VERSION 5.7 ;
  DIVIDERCHAR "/" ;
  BUSBITCHARS "[]" ;
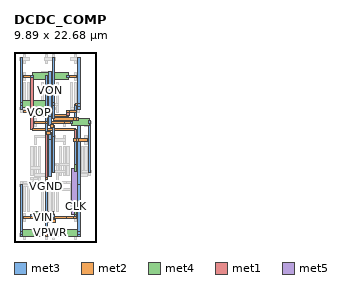
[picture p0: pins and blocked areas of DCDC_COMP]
MACRO DCDC_COMP
  CLASS BLOCK ;
  ORIGIN 0 0 ;
  FOREIGN DCDC_COMP 0 0 ;
  SIZE 9.89 BY 22.68 ;
  PIN VOP
    DIRECTION INOUT ;
    USE SIGNAL ;
    PORT
      LAYER met3 ;
        RECT 3.73 15.38 4.01 19.9 ;
      LAYER met3 ;
        RECT 4.16 7.82 4.44 12.34 ;
      LAYER met2 ;
        RECT 1.12 15.4 2.32 15.68 ;
      LAYER met3 ;
        RECT 3.73 13.02 4.01 15.4 ;
      LAYER met2 ;
        RECT 3.87 12.88 4.3 13.16 ;
      LAYER met3 ;
        RECT 4.16 12.18 4.44 13.02 ;
      LAYER met3 ;
        RECT 3.73 15.215 4.01 15.585 ;
      LAYER met4 ;
        RECT 2.15 15 3.87 15.8 ;
      LAYER met3 ;
        RECT 2.01 15.349 2.29 15.591 ;
      LAYER met2 ;
        RECT 1.99 15.4 2.31 15.68 ;
    END
  END VOP
  PIN VON
    DIRECTION INOUT ;
    USE SIGNAL ;
    PORT
      LAYER met3 ;
        RECT 4.16 15.8 4.44 20.32 ;
      LAYER met3 ;
        RECT 4.59 8.24 4.87 12.76 ;
      LAYER met2 ;
        RECT 6.28 15.4 7.48 15.68 ;
      LAYER met3 ;
        RECT 4.16 13.86 4.44 15.96 ;
      LAYER met2 ;
        RECT 4.3 13.72 4.73 14 ;
      LAYER met3 ;
        RECT 4.59 12.6 4.87 13.86 ;
      LAYER met3 ;
        RECT 4.16 14.935 4.44 15.305 ;
      LAYER met2 ;
        RECT 4.3 14.98 6.45 15.26 ;
      LAYER met1 ;
        RECT 6.325 15.12 6.575 15.54 ;
      LAYER met2 ;
        RECT 6.29 15.4 6.61 15.68 ;
    END
  END VON
  PIN VPWR
    DIRECTION INOUT ;
    USE SIGNAL ;
    PORT
      LAYER met3 ;
        RECT 4.59 16.22 4.87 22 ;
      LAYER met3 ;
        RECT 7.6 0.68 7.88 6.88 ;
      LAYER met3 ;
        RECT 0.72 15.8 1 22 ;
      LAYER met3 ;
        RECT 7.6 15.8 7.88 22 ;
      LAYER met3 ;
        RECT 0.72 0.68 1 6.88 ;
      LAYER met3 ;
        RECT 4.59 14.7 4.87 16.38 ;
      LAYER met2 ;
        RECT 4.73 14.56 7.74 14.84 ;
      LAYER met3 ;
        RECT 7.6 6.72 7.88 14.7 ;
      LAYER met3 ;
        RECT 4.59 16.315 4.87 16.685 ;
      LAYER met4 ;
        RECT 0.86 16.1 4.73 16.9 ;
      LAYER met3 ;
        RECT 0.72 16.315 1 16.685 ;
      LAYER met2 ;
        RECT 7.15 14.56 7.47 14.84 ;
      LAYER met3 ;
        RECT 7.17 14.7 7.45 16.38 ;
      LAYER met2 ;
        RECT 7.31 16.24 7.74 16.52 ;
      LAYER met3 ;
        RECT 7.6 16.195 7.88 16.565 ;
      LAYER met3 ;
        RECT 7.6 0.915 7.88 1.285 ;
      LAYER met4 ;
        RECT 0.86 0.7 7.74 1.5 ;
      LAYER met3 ;
        RECT 0.72 0.915 1 1.285 ;
    END
  END VPWR
  PIN VGND
    DIRECTION INOUT ;
    USE SIGNAL ;
    PORT
      LAYER met2 ;
        RECT 2.41 14.14 6.19 14.42 ;
      LAYER met2 ;
        RECT 3.7 0.7 4.9 0.98 ;
      LAYER met3 ;
        RECT 8.89 8.24 9.17 14.44 ;
      LAYER met2 ;
        RECT 3.71 14.14 4.03 14.42 ;
      LAYER met1 ;
        RECT 3.745 7.56 3.995 14.28 ;
      LAYER met2 ;
        RECT 3.721 7.42 4.019 7.7 ;
      LAYER met3 ;
        RECT 3.73 0.84 4.01 7.56 ;
      LAYER met2 ;
        RECT 3.71 0.7 4.03 0.98 ;
      LAYER met2 ;
        RECT 6.02 14.14 6.88 14.42 ;
      LAYER met3 ;
        RECT 6.74 14.169 7.02 14.411 ;
      LAYER met4 ;
        RECT 6.88 13.9 9.03 14.7 ;
      LAYER met3 ;
        RECT 8.89 14.115 9.17 14.485 ;
    END
  END VGND
  PIN VIN
    DIRECTION INOUT ;
    USE SIGNAL ;
    PORT
      LAYER met2 ;
        RECT 2.84 2.8 4.04 3.08 ;
    END
  END VIN
  PIN VIP
    DIRECTION INOUT ;
    USE SIGNAL ;
    PORT
      LAYER met2 ;
        RECT 3.7 2.38 4.9 2.66 ;
    END
  END VIP
  PIN CLK
    DIRECTION INOUT ;
    USE SIGNAL ;
    PORT
      LAYER met2 ;
        RECT 7.57 12.04 8.77 12.32 ;
      LAYER met2 ;
        RECT 6.28 2.8 7.48 3.08 ;
      LAYER met2 ;
        RECT 1.12 19.6 2.32 19.88 ;
      LAYER met2 ;
        RECT 6.28 19.6 7.48 19.88 ;
      LAYER met2 ;
        RECT 1.12 2.8 2.32 3.08 ;
      LAYER met2 ;
        RECT 7.31 12.04 7.74 12.32 ;
      LAYER met3 ;
        RECT 7.17 8.8 7.45 12.18 ;
      LAYER met4 ;
        RECT 7.205 8.4 7.505 9.2 ;
      LAYER met5 ;
        RECT 6.81 3.3 7.99 8.8 ;
      LAYER met4 ;
        RECT 7.205 2.9 7.505 3.7 ;
      LAYER met3 ;
        RECT 7.17 2.94 7.45 3.3 ;
      LAYER met2 ;
        RECT 7.15 2.8 7.47 3.08 ;
      LAYER met2 ;
        RECT 7.15 12.04 7.47 12.32 ;
      LAYER met1 ;
        RECT 7.185 12.18 7.435 13.44 ;
      LAYER met2 ;
        RECT 2.15 13.3 7.31 13.58 ;
      LAYER met1 ;
        RECT 2.025 13.44 2.275 19.74 ;
      LAYER met2 ;
        RECT 1.99 19.6 2.31 19.88 ;
      LAYER met2 ;
        RECT 1.99 19.6 2.31 19.88 ;
      LAYER met3 ;
        RECT 2.01 19.649 2.29 19.891 ;
      LAYER met4 ;
        RECT 2.15 19.4 6.45 20.2 ;
      LAYER met3 ;
        RECT 6.31 19.649 6.59 19.891 ;
      LAYER met2 ;
        RECT 6.29 19.6 6.61 19.88 ;
      LAYER met2 ;
        RECT 4.73 2.8 6.45 3.08 ;
      LAYER met3 ;
        RECT 4.59 2.94 4.87 3.3 ;
      LAYER met4 ;
        RECT 2.15 2.9 4.73 3.7 ;
      LAYER met3 ;
        RECT 2.01 2.94 2.29 3.3 ;
      LAYER met2 ;
        RECT 1.99 2.8 2.31 3.08 ;
    END
  END CLK
  OBS
  LAYER met2 ;
        RECT 1.98 8.68 3.18 8.96 ;
  LAYER met2 ;
        RECT 2.84 7 4.04 7.28 ;
  LAYER met2 ;
        RECT 1.12 7 2.32 7.28 ;
  LAYER met2 ;
        RECT 2.85 8.68 3.17 8.96 ;
  LAYER met3 ;
        RECT 2.87 7.14 3.15 8.82 ;
  LAYER met2 ;
        RECT 2.85 7 3.17 7.28 ;
  LAYER met3 ;
        RECT 2.87 7.375 3.15 7.745 ;
  LAYER met2 ;
        RECT 2.15 7.42 3.01 7.7 ;
  LAYER met1 ;
        RECT 2.025 7.14 2.275 7.56 ;
  LAYER met2 ;
        RECT 1.99 7 2.31 7.28 ;
  LAYER met2 ;
        RECT 2.85 7 3.17 7.28 ;
  LAYER met3 ;
        RECT 2.87 6.98 3.15 7.3 ;
  LAYER met2 ;
        RECT 2.85 8.68 3.17 8.96 ;
  LAYER met3 ;
        RECT 2.87 8.66 3.15 8.98 ;
  LAYER met2 ;
        RECT 2.85 7 3.17 7.28 ;
  LAYER met3 ;
        RECT 2.87 6.98 3.15 7.3 ;
  LAYER met2 ;
        RECT 2.85 8.68 3.17 8.96 ;
  LAYER met3 ;
        RECT 2.87 8.66 3.15 8.98 ;
  LAYER met1 ;
        RECT 2.025 7.055 2.275 7.225 ;
  LAYER met2 ;
        RECT 1.98 7 2.32 7.28 ;
  LAYER met1 ;
        RECT 2.025 7.475 2.275 7.645 ;
  LAYER met2 ;
        RECT 1.98 7.42 2.32 7.7 ;
  LAYER met2 ;
        RECT 2.85 7 3.17 7.28 ;
  LAYER met3 ;
        RECT 2.87 6.98 3.15 7.3 ;
  LAYER met2 ;
        RECT 2.85 7.42 3.17 7.7 ;
  LAYER met3 ;
        RECT 2.87 7.4 3.15 7.72 ;
  LAYER met2 ;
        RECT 2.85 8.68 3.17 8.96 ;
  LAYER met3 ;
        RECT 2.87 8.66 3.15 8.98 ;
  LAYER met1 ;
        RECT 2.025 7.055 2.275 7.225 ;
  LAYER met2 ;
        RECT 1.98 7 2.32 7.28 ;
  LAYER met1 ;
        RECT 2.025 7.475 2.275 7.645 ;
  LAYER met2 ;
        RECT 1.98 7.42 2.32 7.7 ;
  LAYER met2 ;
        RECT 2.85 7 3.17 7.28 ;
  LAYER met3 ;
        RECT 2.87 6.98 3.15 7.3 ;
  LAYER met2 ;
        RECT 2.85 7.42 3.17 7.7 ;
  LAYER met3 ;
        RECT 2.87 7.4 3.15 7.72 ;
  LAYER met2 ;
        RECT 2.85 8.68 3.17 8.96 ;
  LAYER met3 ;
        RECT 2.87 8.66 3.15 8.98 ;
  LAYER met2 ;
        RECT 5.42 9.1 6.62 9.38 ;
  LAYER met2 ;
        RECT 3.7 6.58 4.9 6.86 ;
  LAYER met2 ;
        RECT 6.28 7 7.48 7.28 ;
  LAYER met2 ;
        RECT 5.16 9.1 5.59 9.38 ;
  LAYER met3 ;
        RECT 5.02 6.72 5.3 9.24 ;
  LAYER met2 ;
        RECT 4.73 6.58 5.16 6.86 ;
  LAYER met3 ;
        RECT 5.02 6.955 5.3 7.325 ;
  LAYER met2 ;
        RECT 5.16 7 6.45 7.28 ;
  LAYER met2 ;
        RECT 5 6.58 5.32 6.86 ;
  LAYER met3 ;
        RECT 5.02 6.56 5.3 6.88 ;
  LAYER met2 ;
        RECT 5 9.1 5.32 9.38 ;
  LAYER met3 ;
        RECT 5.02 9.08 5.3 9.4 ;
  LAYER met2 ;
        RECT 5 6.58 5.32 6.86 ;
  LAYER met3 ;
        RECT 5.02 6.56 5.3 6.88 ;
  LAYER met2 ;
        RECT 5 9.1 5.32 9.38 ;
  LAYER met3 ;
        RECT 5.02 9.08 5.3 9.4 ;
  LAYER met2 ;
        RECT 5 6.58 5.32 6.86 ;
  LAYER met3 ;
        RECT 5.02 6.56 5.3 6.88 ;
  LAYER met2 ;
        RECT 5 7 5.32 7.28 ;
  LAYER met3 ;
        RECT 5.02 6.98 5.3 7.3 ;
  LAYER met2 ;
        RECT 5 9.1 5.32 9.38 ;
  LAYER met3 ;
        RECT 5.02 9.08 5.3 9.4 ;
  LAYER met2 ;
        RECT 5 6.58 5.32 6.86 ;
  LAYER met3 ;
        RECT 5.02 6.56 5.3 6.88 ;
  LAYER met2 ;
        RECT 5 7 5.32 7.28 ;
  LAYER met3 ;
        RECT 5.02 6.98 5.3 7.3 ;
  LAYER met2 ;
        RECT 5 9.1 5.32 9.38 ;
  LAYER met3 ;
        RECT 5.02 9.08 5.3 9.4 ;
  LAYER met2 ;
        RECT 3.27 6.16 5.33 6.44 ;
  LAYER met2 ;
        RECT 7.57 7.84 8.77 8.12 ;
  LAYER met2 ;
        RECT 5.16 6.16 7.31 6.44 ;
  LAYER met3 ;
        RECT 7.17 6.3 7.45 7.98 ;
  LAYER met2 ;
        RECT 7.31 7.84 7.74 8.12 ;
  LAYER met2 ;
        RECT 7.15 6.16 7.47 6.44 ;
  LAYER met3 ;
        RECT 7.17 6.14 7.45 6.46 ;
  LAYER met2 ;
        RECT 7.15 7.84 7.47 8.12 ;
  LAYER met3 ;
        RECT 7.17 7.82 7.45 8.14 ;
  LAYER met2 ;
        RECT 7.15 6.16 7.47 6.44 ;
  LAYER met3 ;
        RECT 7.17 6.14 7.45 6.46 ;
  LAYER met2 ;
        RECT 7.15 7.84 7.47 8.12 ;
  LAYER met3 ;
        RECT 7.17 7.82 7.45 8.14 ;
  LAYER met1 ;
        RECT 3.745 15.455 3.995 18.985 ;
  LAYER met1 ;
        RECT 3.745 19.235 3.995 20.245 ;
  LAYER met1 ;
        RECT 3.745 21.335 3.995 22.345 ;
  LAYER met1 ;
        RECT 3.315 15.455 3.565 18.985 ;
  LAYER met1 ;
        RECT 4.175 15.455 4.425 18.985 ;
  LAYER met1 ;
        RECT 4.605 15.455 4.855 18.985 ;
  LAYER met1 ;
        RECT 4.605 19.235 4.855 20.245 ;
  LAYER met1 ;
        RECT 4.605 21.335 4.855 22.345 ;
  LAYER met1 ;
        RECT 5.035 15.455 5.285 18.985 ;
  LAYER met2 ;
        RECT 2.84 15.4 4.04 15.68 ;
  LAYER met2 ;
        RECT 3.7 19.6 4.9 19.88 ;
  LAYER met2 ;
        RECT 3.7 15.82 4.9 16.1 ;
  LAYER met2 ;
        RECT 3.27 20.02 4.47 20.3 ;
  LAYER met2 ;
        RECT 3.27 16.24 5.33 16.52 ;
  LAYER met2 ;
        RECT 3.7 21.7 4.9 21.98 ;
  LAYER met3 ;
        RECT 3.73 15.38 4.01 19.9 ;
  LAYER met3 ;
        RECT 4.16 15.8 4.44 20.32 ;
  LAYER met3 ;
        RECT 4.59 16.22 4.87 22 ;
  LAYER met1 ;
        RECT 2.455 7.895 2.705 11.425 ;
  LAYER met1 ;
        RECT 2.455 11.675 2.705 12.685 ;
  LAYER met1 ;
        RECT 2.455 13.775 2.705 14.785 ;
  LAYER met1 ;
        RECT 2.025 7.895 2.275 11.425 ;
  LAYER met1 ;
        RECT 2.885 7.895 3.135 11.425 ;
  LAYER met1 ;
        RECT 5.895 7.895 6.145 11.425 ;
  LAYER met1 ;
        RECT 5.895 11.675 6.145 12.685 ;
  LAYER met1 ;
        RECT 5.895 13.775 6.145 14.785 ;
  LAYER met1 ;
        RECT 5.465 7.895 5.715 11.425 ;
  LAYER met1 ;
        RECT 6.325 7.895 6.575 11.425 ;
  LAYER met2 ;
        RECT 2.41 7.84 4.47 8.12 ;
  LAYER met2 ;
        RECT 4.13 12.04 6.19 12.32 ;
  LAYER met2 ;
        RECT 4.56 8.26 6.19 8.54 ;
  LAYER met2 ;
        RECT 2.41 12.46 4.9 12.74 ;
  LAYER met2 ;
        RECT 2.41 14.14 6.19 14.42 ;
  LAYER met3 ;
        RECT 4.16 7.82 4.44 12.34 ;
  LAYER met3 ;
        RECT 4.59 8.24 4.87 12.76 ;
  LAYER met2 ;
        RECT 1.98 8.68 3.18 8.96 ;
  LAYER met2 ;
        RECT 5.42 9.1 6.62 9.38 ;
  LAYER met1 ;
        RECT 3.745 3.695 3.995 7.225 ;
  LAYER met1 ;
        RECT 3.745 2.435 3.995 3.445 ;
  LAYER met1 ;
        RECT 3.745 0.335 3.995 1.345 ;
  LAYER met1 ;
        RECT 3.315 3.695 3.565 7.225 ;
  LAYER met1 ;
        RECT 4.175 3.695 4.425 7.225 ;
  LAYER met1 ;
        RECT 4.605 3.695 4.855 7.225 ;
  LAYER met1 ;
        RECT 4.605 2.435 4.855 3.445 ;
  LAYER met1 ;
        RECT 4.605 0.335 4.855 1.345 ;
  LAYER met1 ;
        RECT 5.035 3.695 5.285 7.225 ;
  LAYER met2 ;
        RECT 3.7 0.7 4.9 0.98 ;
  LAYER met2 ;
        RECT 2.84 7 4.04 7.28 ;
  LAYER met2 ;
        RECT 3.7 6.58 4.9 6.86 ;
  LAYER met2 ;
        RECT 2.84 2.8 4.04 3.08 ;
  LAYER met2 ;
        RECT 3.7 2.38 4.9 2.66 ;
  LAYER met2 ;
        RECT 3.27 6.16 5.33 6.44 ;
  LAYER met1 ;
        RECT 8.475 7.895 8.725 11.425 ;
  LAYER met1 ;
        RECT 8.475 11.675 8.725 12.685 ;
  LAYER met1 ;
        RECT 8.475 13.775 8.725 14.785 ;
  LAYER met1 ;
        RECT 8.045 7.895 8.295 11.425 ;
  LAYER met1 ;
        RECT 8.905 7.895 9.155 11.425 ;
  LAYER met2 ;
        RECT 8 8.26 9.2 8.54 ;
  LAYER met2 ;
        RECT 8 14.14 9.2 14.42 ;
  LAYER met2 ;
        RECT 7.57 7.84 8.77 8.12 ;
  LAYER met2 ;
        RECT 7.57 12.04 8.77 12.32 ;
  LAYER met3 ;
        RECT 8.89 8.24 9.17 14.44 ;
  LAYER met1 ;
        RECT 7.185 3.695 7.435 7.225 ;
  LAYER met1 ;
        RECT 7.185 2.435 7.435 3.445 ;
  LAYER met1 ;
        RECT 7.185 0.335 7.435 1.345 ;
  LAYER met1 ;
        RECT 6.755 3.695 7.005 7.225 ;
  LAYER met1 ;
        RECT 7.615 3.695 7.865 7.225 ;
  LAYER met2 ;
        RECT 6.71 6.58 7.91 6.86 ;
  LAYER met2 ;
        RECT 6.71 0.7 7.91 0.98 ;
  LAYER met2 ;
        RECT 6.28 7 7.48 7.28 ;
  LAYER met2 ;
        RECT 6.28 2.8 7.48 3.08 ;
  LAYER met3 ;
        RECT 7.6 0.68 7.88 6.88 ;
  LAYER met1 ;
        RECT 1.165 15.455 1.415 18.985 ;
  LAYER met1 ;
        RECT 1.165 19.235 1.415 20.245 ;
  LAYER met1 ;
        RECT 1.165 21.335 1.415 22.345 ;
  LAYER met1 ;
        RECT 1.595 15.455 1.845 18.985 ;
  LAYER met1 ;
        RECT 0.735 15.455 0.985 18.985 ;
  LAYER met2 ;
        RECT 0.69 15.82 1.89 16.1 ;
  LAYER met2 ;
        RECT 0.69 21.7 1.89 21.98 ;
  LAYER met2 ;
        RECT 1.12 15.4 2.32 15.68 ;
  LAYER met2 ;
        RECT 1.12 19.6 2.32 19.88 ;
  LAYER met3 ;
        RECT 0.72 15.8 1 22 ;
  LAYER met1 ;
        RECT 7.185 15.455 7.435 18.985 ;
  LAYER met1 ;
        RECT 7.185 19.235 7.435 20.245 ;
  LAYER met1 ;
        RECT 7.185 21.335 7.435 22.345 ;
  LAYER met1 ;
        RECT 6.755 15.455 7.005 18.985 ;
  LAYER met1 ;
        RECT 7.615 15.455 7.865 18.985 ;
  LAYER met2 ;
        RECT 6.71 15.82 7.91 16.1 ;
  LAYER met2 ;
        RECT 6.71 21.7 7.91 21.98 ;
  LAYER met2 ;
        RECT 6.28 15.4 7.48 15.68 ;
  LAYER met2 ;
        RECT 6.28 19.6 7.48 19.88 ;
  LAYER met3 ;
        RECT 7.6 15.8 7.88 22 ;
  LAYER met1 ;
        RECT 1.165 3.695 1.415 7.225 ;
  LAYER met1 ;
        RECT 1.165 2.435 1.415 3.445 ;
  LAYER met1 ;
        RECT 1.165 0.335 1.415 1.345 ;
  LAYER met1 ;
        RECT 1.595 3.695 1.845 7.225 ;
  LAYER met1 ;
        RECT 0.735 3.695 0.985 7.225 ;
  LAYER met2 ;
        RECT 0.69 6.58 1.89 6.86 ;
  LAYER met2 ;
        RECT 0.69 0.7 1.89 0.98 ;
  LAYER met2 ;
        RECT 1.12 7 2.32 7.28 ;
  LAYER met2 ;
        RECT 1.12 2.8 2.32 3.08 ;
  LAYER met3 ;
        RECT 0.72 0.68 1 6.88 ;
  END
END DCDC_COMP
